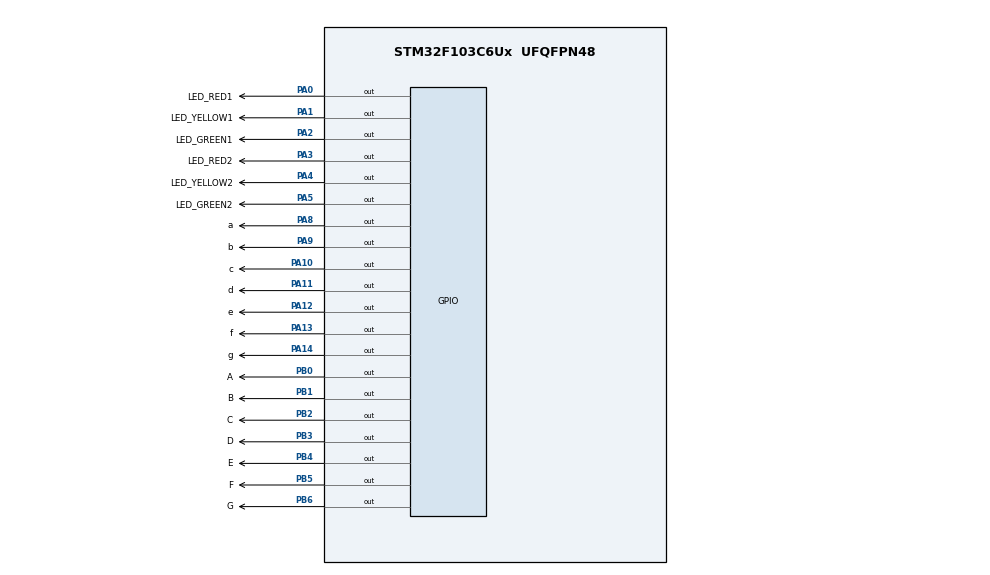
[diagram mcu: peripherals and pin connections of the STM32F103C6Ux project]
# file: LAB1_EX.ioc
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Mcu.Family=STM32F1
Mcu.Name=STM32F103C6Ux
Mcu.Package=UFQFPN48
NVIC.PriorityGroup=NVIC_PRIORITYGROUP_4
PA0-WKUP.GPIO_Label=LED_RED1
PA0-WKUP.Signal=GPIO_Output
PA1.GPIO_Label=LED_YELLOW1
PA1.Signal=GPIO_Output
PA10.GPIO_Label=c
PA10.Signal=GPIO_Output
PA11.GPIO_Label=d
PA11.Signal=GPIO_Output
PA12.GPIO_Label=e
PA12.Signal=GPIO_Output
PA13.GPIO_Label=f
PA13.Signal=GPIO_Output
PA14.GPIO_Label=g
PA14.Signal=GPIO_Output
PA2.GPIO_Label=LED_GREEN1
PA2.Signal=GPIO_Output
PA3.GPIO_Label=LED_RED2
PA3.Signal=GPIO_Output
PA4.GPIO_Label=LED_YELLOW2
PA4.Signal=GPIO_Output
PA5.GPIO_Label=LED_GREEN2
PA5.Signal=GPIO_Output
PA8.GPIO_Label=a
PA8.Signal=GPIO_Output
PA9.GPIO_Label=b
PA9.Signal=GPIO_Output
PB0.GPIO_Label=A
PB0.Signal=GPIO_Output
PB1.GPIO_Label=B
PB1.Signal=GPIO_Output
PB2.GPIO_Label=C
PB2.Signal=GPIO_Output
PB3.GPIO_Label=D
PB3.Signal=GPIO_Output
PB4.GPIO_Label=E
PB4.Signal=GPIO_Output
PB5.GPIO_Label=F
PB5.Signal=GPIO_Output
PB6.GPIO_Label=G
PB6.Signal=GPIO_Output
ProjectManager.HeapSize=0x200
ProjectManager.StackSize=0x400
ProjectManager.TargetToolchain=STM32CubeIDE
RCC.APB1Freq_Value=8000000
RCC.APB2Freq_Value=8000000
VP_SYS_VS_ND.Mode=No_Debug
board=custom

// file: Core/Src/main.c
/* USER CODE BEGIN Header */
/**
  ******************************************************************************
  * @file           : main.c
  * @brief          : Main program body
  ******************************************************************************
  * @attention
  *
  * <h2><center>&copy; Copyright (c) 2023 STMicroelectronics.
  * All rights reserved.</center></h2>
  *
  * This software component is licensed by ST under BSD 3-Clause license,
  * the "License"; You may not use this file except in compliance with the
  * License. You may obtain a copy of the License at:
  *                        opensource.org/licenses/BSD-3-Clause
  *
  ******************************************************************************
  */
/* USER CODE END Header */
#include "main.h"

void SystemClock_Config(void);
static void MX_GPIO_Init(void);

int main(void)
{

  /* MCU Configuration--------------------------------------------------------*/

  /* Reset of all peripherals, Initializes the Flash interface and the Systick. */
  HAL_Init();

  /* Configure the system clock */
  SystemClock_Config();

  /* Initialize all configured peripherals */
  MX_GPIO_Init();

  /* Infinite loop */
  /* USER CODE BEGIN WHILE */
  int NUM[12][12],i,j,h;
      for (i=0;i<12;i++)
      {
      for (j=0;j<12;j++)
      {
      	NUM[i][j]=1;}
        NUM[i][i]=1;
      }
      void clearNumberOnClock(int num)
     		  {
     		  	HAL_GPIO_WritePin ( a_GPIO_Port , a_Pin  ,NUM[num] [0] );
     		  	HAL_GPIO_WritePin ( b_GPIO_Port , b_Pin  ,NUM[num] [1] );
     		  	HAL_GPIO_WritePin ( c_GPIO_Port , c_Pin  ,NUM[num] [2] );
     		  	HAL_GPIO_WritePin ( d_GPIO_Port , d_Pin  ,NUM[num] [3] );
     		  	HAL_GPIO_WritePin ( e_GPIO_Port , e_Pin  ,NUM[num] [4] );
     		  	HAL_GPIO_WritePin ( f_GPIO_Port , f_Pin  ,NUM[num] [5] );
     		  	HAL_GPIO_WritePin ( g_GPIO_Port , g_Pin  ,NUM[num] [6] );
     		  	HAL_GPIO_WritePin ( h_GPIO_Port , h_Pin  ,NUM[num] [7] );
     		    HAL_GPIO_WritePin ( i_GPIO_Port , i_Pin  ,NUM[num] [8] );
     		    HAL_GPIO_WritePin ( k_GPIO_Port , k_Pin  ,NUM[num] [9] );
     		    HAL_GPIO_WritePin ( l_GPIO_Port , l_Pin  ,NUM[num] [10] );
     		    HAL_GPIO_WritePin ( m_GPIO_Port , m_Pin  ,NUM[num] [11] );
     		  };
  while (1)
  {
	  h=0+rand()%12;
	  NUM[h][h]=0;
	  clearNumberOnClock(h);
	   HAL_Delay(1000);
  }
  /* USER CODE END 3 */
}

void SystemClock_Config(void)
{
  RCC_OscInitTypeDef RCC_OscInitStruct = {0};
  RCC_ClkInitTypeDef RCC_ClkInitStruct = {0};

  /** Initializes the RCC Oscillators according to the specified parameters
  * in the RCC_OscInitTypeDef structure.
  */
  RCC_OscInitStruct.OscillatorType = RCC_OSCILLATORTYPE_HSI;
  RCC_OscInitStruct.HSIState = RCC_HSI_ON;
  RCC_OscInitStruct.HSICalibrationValue = RCC_HSICALIBRATION_DEFAULT;
  RCC_OscInitStruct.PLL.PLLState = RCC_PLL_NONE;
  if (HAL_RCC_OscConfig(&RCC_OscInitStruct) != HAL_OK)
  {
    Error_Handler();
  }
  /** Initializes the CPU, AHB and APB buses clocks
  */
  RCC_ClkInitStruct.ClockType = RCC_CLOCKTYPE_HCLK|RCC_CLOCKTYPE_SYSCLK
                              |RCC_CLOCKTYPE_PCLK1|RCC_CLOCKTYPE_PCLK2;
  RCC_ClkInitStruct.SYSCLKSource = RCC_SYSCLKSOURCE_HSI;
  RCC_ClkInitStruct.AHBCLKDivider = RCC_SYSCLK_DIV1;
  RCC_ClkInitStruct.APB1CLKDivider = RCC_HCLK_DIV1;
  RCC_ClkInitStruct.APB2CLKDivider = RCC_HCLK_DIV1;

  if (HAL_RCC_ClockConfig(&RCC_ClkInitStruct, FLASH_LATENCY_0) != HAL_OK)
  {
    Error_Handler();
  }
}

static void MX_GPIO_Init(void)
{
  GPIO_InitTypeDef GPIO_InitStruct = {0};

  /* GPIO Ports Clock Enable */
  __HAL_RCC_GPIOA_CLK_ENABLE();

  /*Configure GPIO pin Output Level */
  HAL_GPIO_WritePin(GPIOA, a_Pin|b_Pin|c_Pin|d_Pin
                          |e_Pin|f_Pin|g_Pin|h_Pin
                          |i_Pin|k_Pin|l_Pin|m_Pin, GPIO_PIN_RESET);

  /*Configure GPIO pins : a_Pin b_Pin c_Pin d_Pin
                           e_Pin f_Pin g_Pin h_Pin
                           i_Pin k_Pin l_Pin m_Pin */
  GPIO_InitStruct.Pin = a_Pin|b_Pin|c_Pin|d_Pin
                          |e_Pin|f_Pin|g_Pin|h_Pin
                          |i_Pin|k_Pin|l_Pin|m_Pin;
  GPIO_InitStruct.Mode = GPIO_MODE_OUTPUT_PP;
  GPIO_InitStruct.Pull = GPIO_NOPULL;
  GPIO_InitStruct.Speed = GPIO_SPEED_FREQ_LOW;
  HAL_GPIO_Init(GPIOA, &GPIO_InitStruct);

}

void Error_Handler(void)
{
  __disable_irq();
  while (1)
  {
  }
}

/************************ (C) COPYRIGHT STMicroelectronics *****END OF FILE****/
